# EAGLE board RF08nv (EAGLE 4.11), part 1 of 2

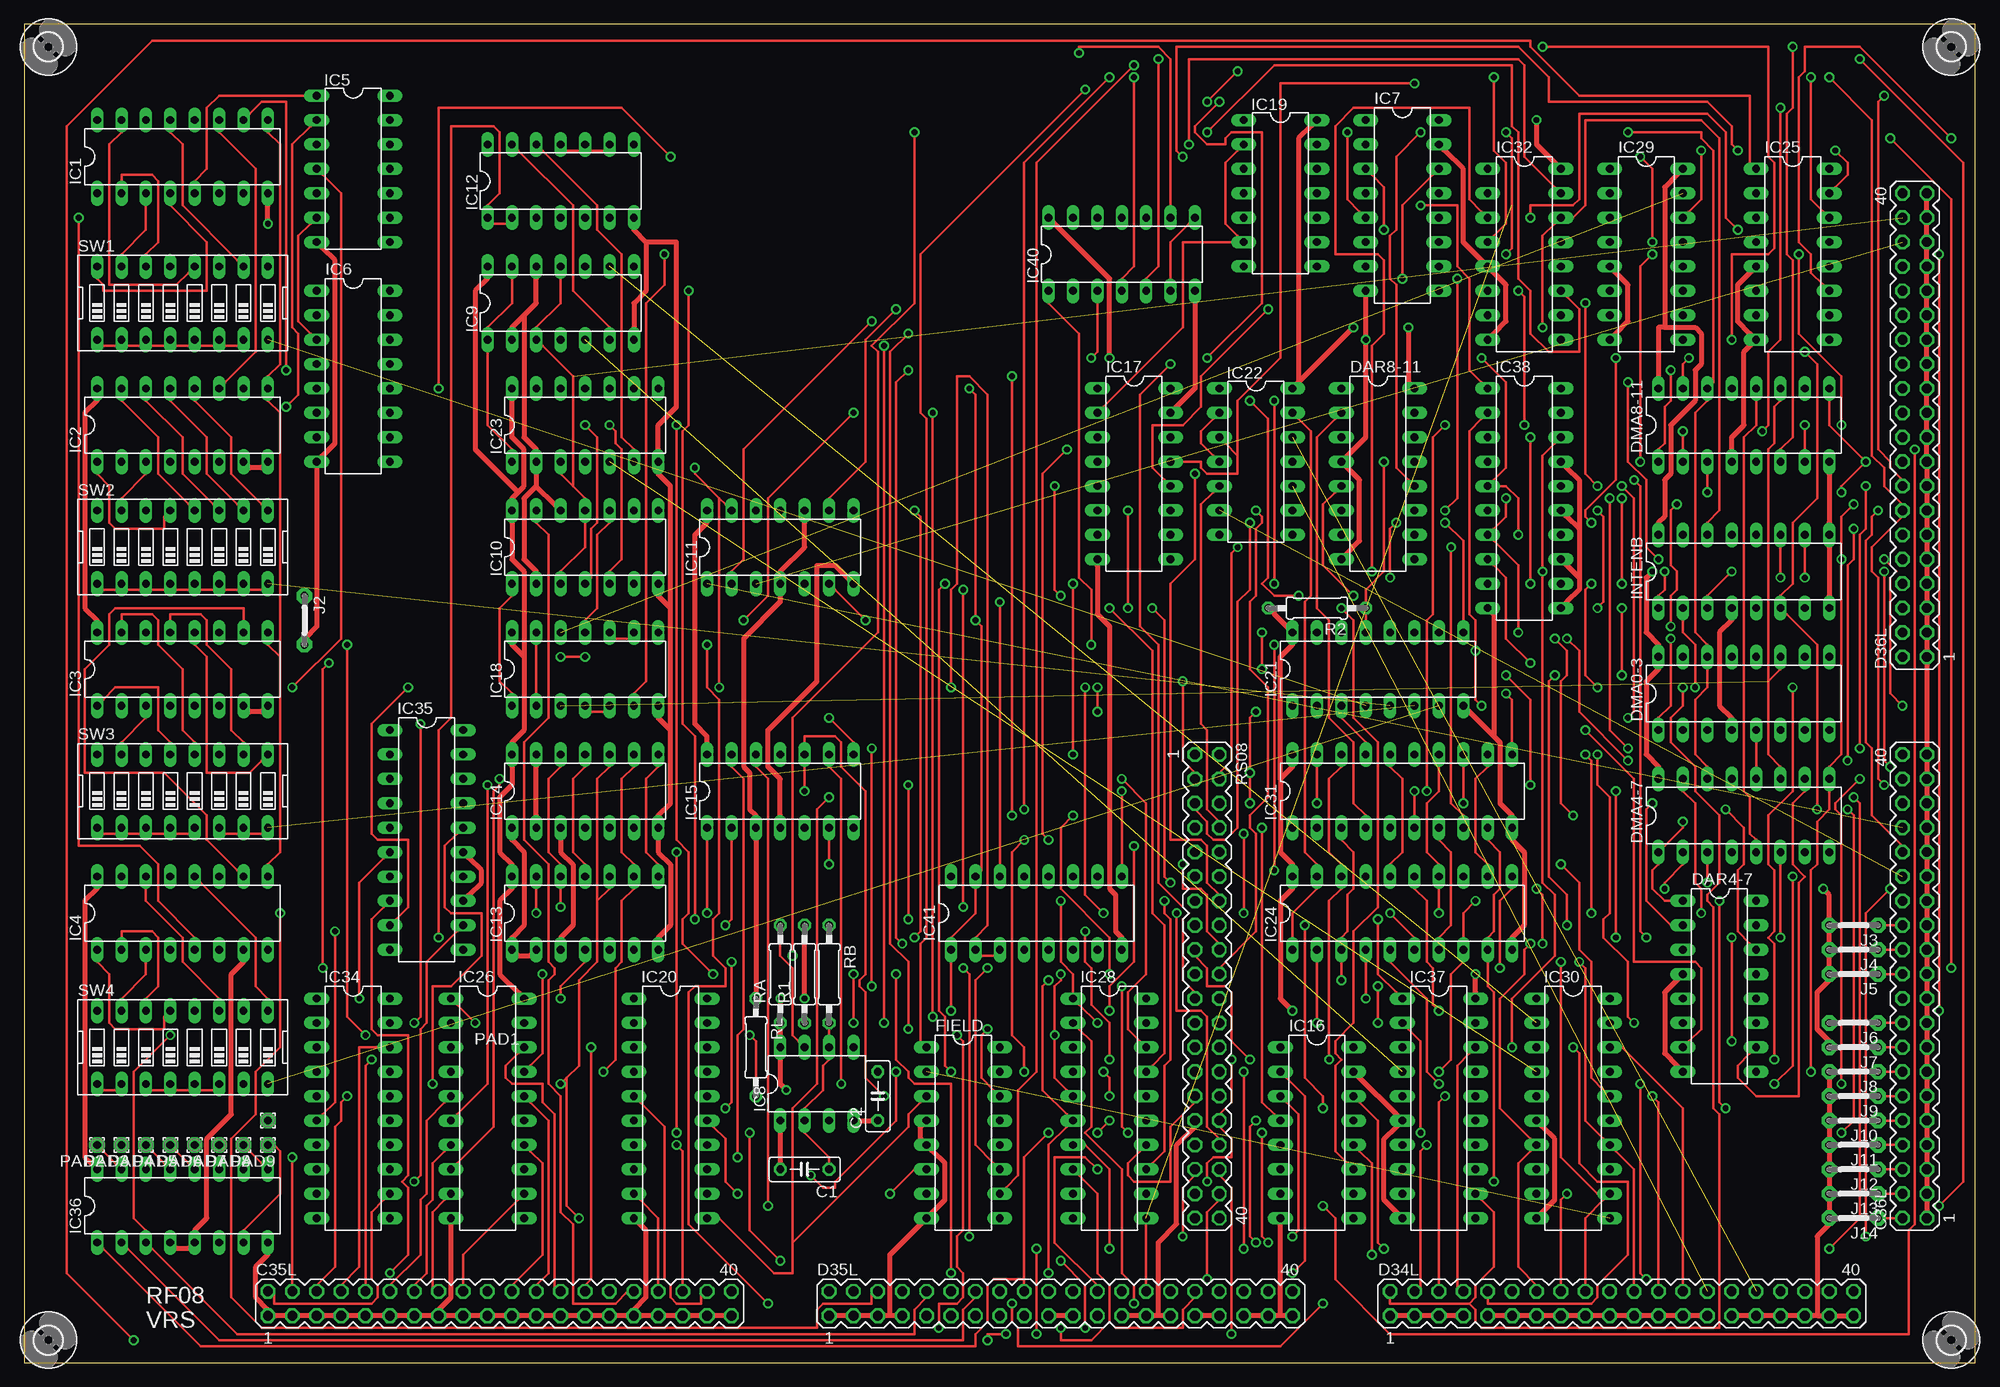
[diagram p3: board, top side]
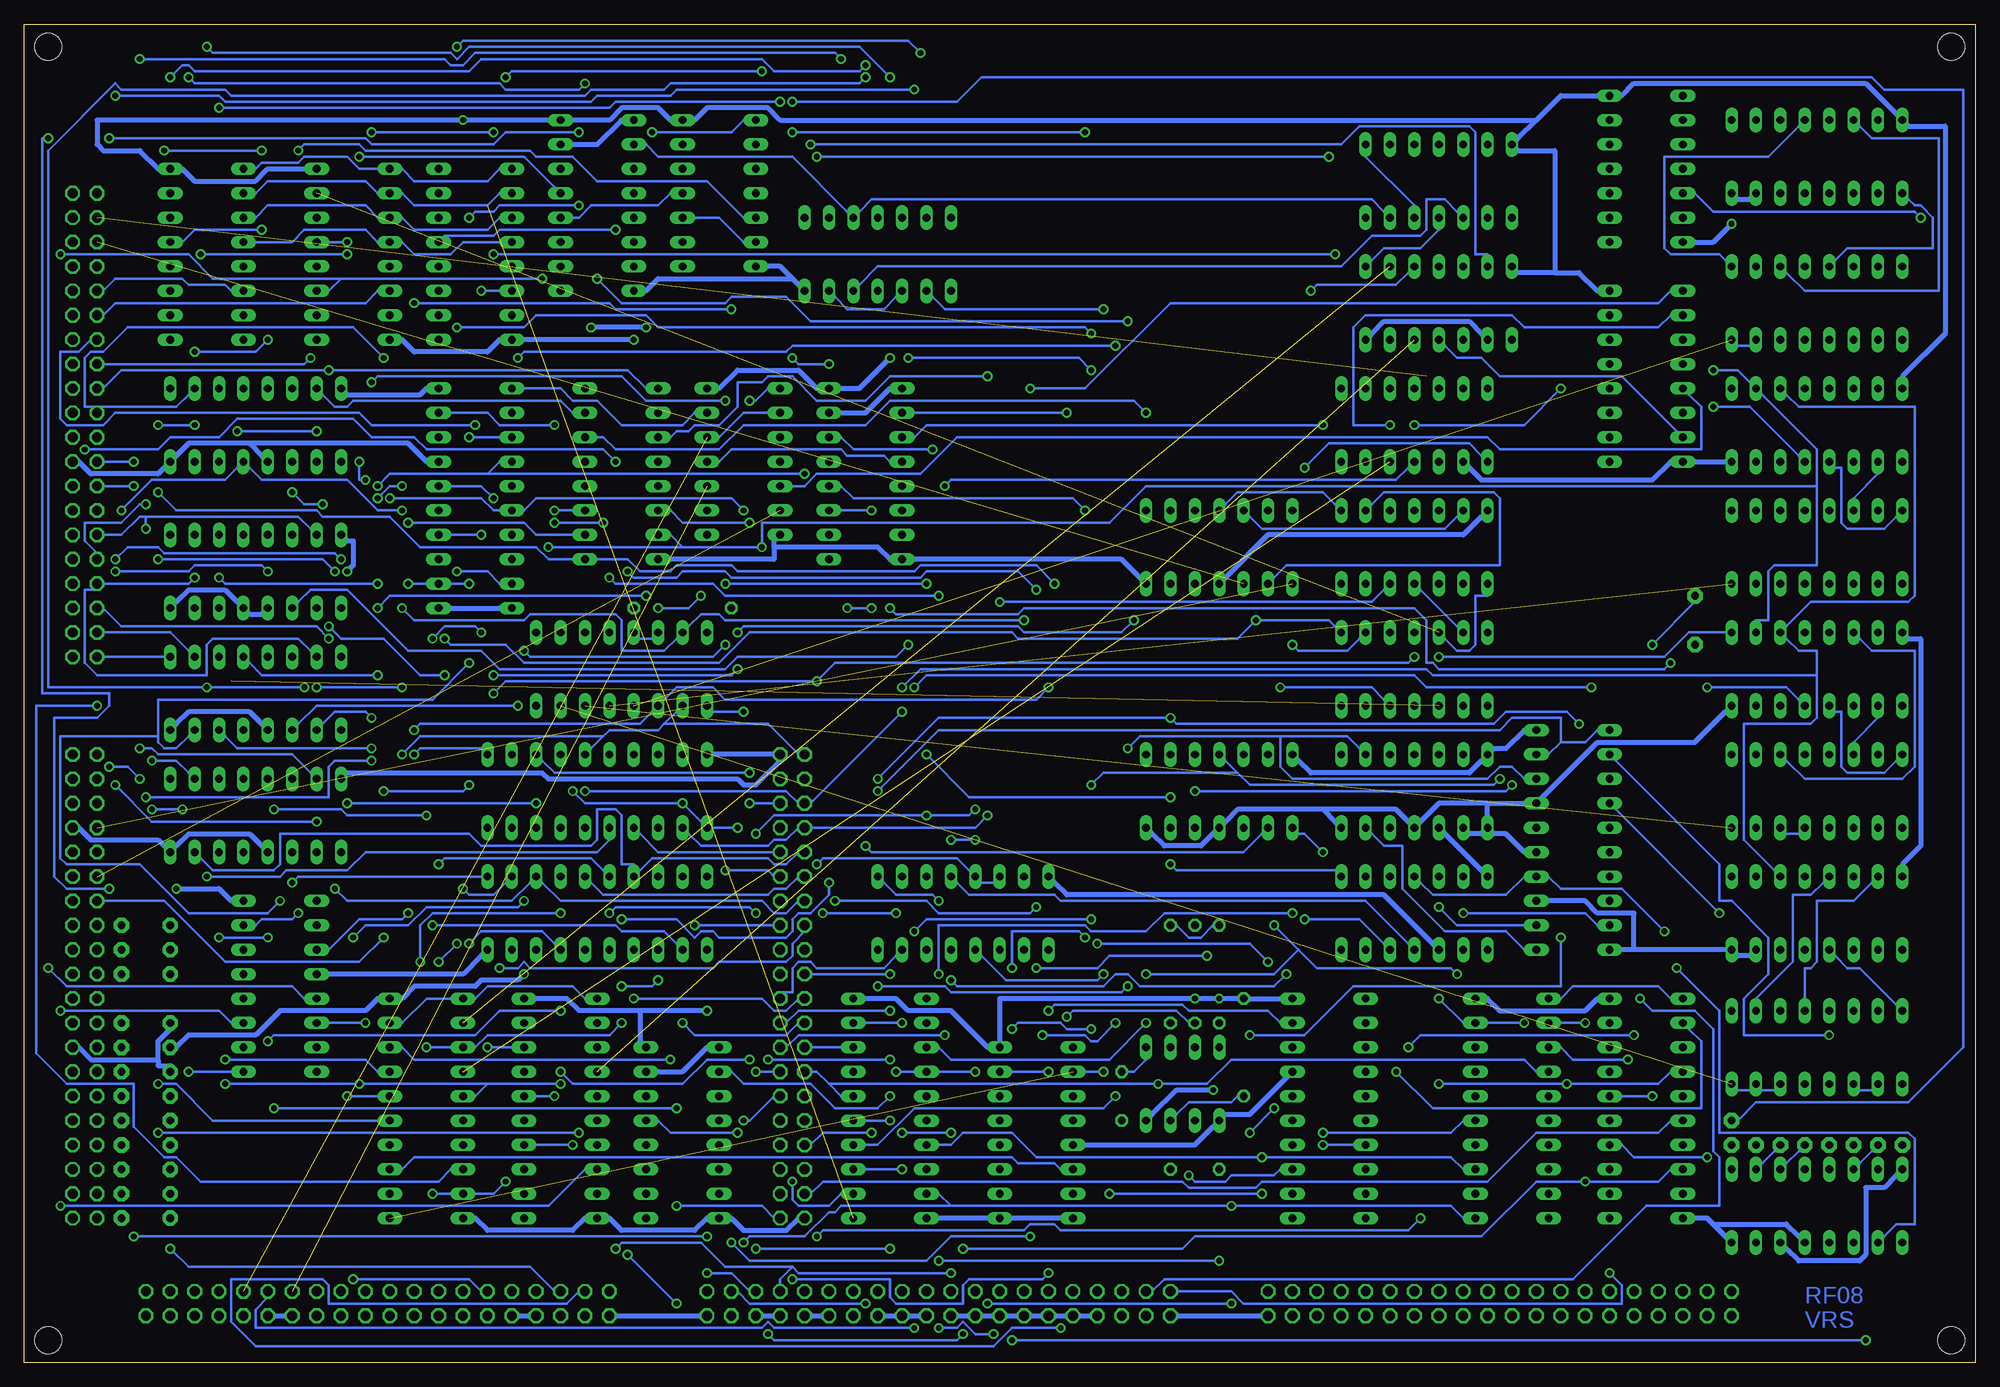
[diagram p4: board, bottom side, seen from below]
Size 203.18 x 139.37 mm. Coordinates in mm from the lower left corner, seen from the top.
Outline: 0,0 203.18,0 203.18,139.37 0,139.37 0,0
Copper layers (1*16): Top 0.035mm / dielectric 1.5mm / Bottom 0.035mm
Design rules "default": minimum track width 10mil, minimum drill 24mil, track to track 8mil, track to pad 8mil, pad to pad 8mil, via to via 8mil, smd to smd 8mil, copper to edge 40mil, drill to drill 8mil, minimum pad ring 10mil, minimum via ring 8mil, stop-mask expansion 4mil, vias tented up to drill 0mil, thermal gap 10mil
Net classes: 1 Power: width 0.508 mm

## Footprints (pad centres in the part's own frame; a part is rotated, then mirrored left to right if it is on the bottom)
C050-025X075 = drill 0.813 octagon: 1 -2.54,0; 2 2.54,0
MA20-2 = drill 1.016 octagon: 1 -24.13,-1.27; 2 -24.13,1.27; 3 -21.59,-1.27; 4 -21.59,1.27; 5 -19.05,-1.27; 6 -19.05,1.27; 7 -16.51,-1.27; 8 -16.51,1.27; 9 -13.97,-1.27; 10 -13.97,1.27; 11 -11.43,-1.27; 12 -11.43,1.27; 13 -8.89,-1.27; 14 -8.89,1.27; 15 -6.35,-1.27; 16 -6.35,1.27; 17 -3.81,-1.27; 18 -3.81,1.27; 19 -1.27,-1.27; 20 -1.27,1.27; 21 1.27,-1.27; 22 1.27,1.27; 23 3.81,-1.27; 24 3.81,1.27; 25 6.35,-1.27; 26 6.35,1.27; 27 8.89,-1.27; 28 8.89,1.27; 29 11.43,-1.27; 30 11.43,1.27; 31 13.97,-1.27; 32 13.97,1.27; 33 16.51,-1.27; 34 16.51,1.27; 35 19.05,-1.27; 36 19.05,1.27; 37 21.59,-1.27; 38 21.59,1.27; 39 24.13,-1.27; 40 24.13,1.27
DIL16 = drill 0.813 long: 1 -8.89,-3.81; 2 -6.35,-3.81; 3 -3.81,-3.81; 4 -1.27,-3.81; 5 1.27,-3.81; 6 3.81,-3.81; 7 6.35,-3.81; 8 8.89,-3.81; 9 8.89,3.81; 10 6.35,3.81; 11 3.81,3.81; 12 1.27,3.81; 13 -1.27,3.81; 14 -3.81,3.81; 15 -6.35,3.81; 16 -8.89,3.81
DIL14 = drill 0.813 long: 1 -7.62,-3.81; 2 -5.08,-3.81; 3 -2.54,-3.81; 4 0,-3.81; 5 2.54,-3.81; 6 5.08,-3.81; 7 7.62,-3.81; 8 7.62,3.81; 9 5.08,3.81; 10 2.54,3.81; 11 0,3.81; 12 -2.54,3.81; 13 -5.08,3.81; 14 -7.62,3.81
DIL08 = drill 0.813 long: 1 -3.81,-3.81; 2 -1.27,-3.81; 3 1.27,-3.81; 4 3.81,-3.81; 5 3.81,3.81; 6 1.27,3.81; 7 -1.27,3.81; 8 -3.81,3.81
DIL20 = drill 0.813 long: 1 -11.43,-3.81; 2 -8.89,-3.81; 3 -6.35,-3.81; 4 -3.81,-3.81; 5 -1.27,-3.81; 6 1.27,-3.81; 7 3.81,-3.81; 8 6.35,-3.81; 9 8.89,-3.81; 10 11.43,-3.81; 11 11.43,3.81; 12 8.89,3.81; 13 6.35,3.81; 14 3.81,3.81; 15 1.27,3.81; 16 -1.27,3.81; 17 -3.81,3.81; 18 -6.35,3.81; 19 -8.89,3.81; 20 -11.43,3.81
05 = drill 0.813 pad 1.6 octagon: 1 -2.54,0; 2 2.54,0
1,6/0,8 = drill 0.813 pad 1.6 octagon: 1 0,0
0207/10 = drill 0.813 octagon: 1 -5.08,0; 2 5.08,0
EDG-08 = drill 0.813 long: 1 -8.89,-3.81; 2 -6.35,-3.81; 3 -3.81,-3.81; 4 -1.27,-3.81; 5 1.27,-3.81; 6 3.81,-3.81; 7 6.35,-3.81; 8 8.89,-3.81; 9 8.89,3.81; 10 6.35,3.81; 11 3.81,3.81; 12 1.27,3.81; 13 -1.27,3.81; 14 -3.81,3.81; 15 -6.35,3.81; 16 -8.89,3.81
2,8 = hole 2.8: 0,0

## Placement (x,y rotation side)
C1  .1uf  [C050-025X075]  81.28,20.16 180 top
C2  .1uf  [C050-025X075]  88.9,27.78 90 top
C35L  [MA20-2]  49.52,6.18 0 top
C36L  [MA20-2]  196.84,39.2 90 top
D34L  [MA20-2]  166.37,6.18 0 top
D35L  [MA20-2]  107.95,6.18 0 top
D36L  [MA20-2]  196.84,97.62 90 top
DAR4-7  74LS193N  [DIL16]  176.53,39.2 270 top
DAR8-11  74LS193N  [DIL16]  140.97,92.54 270 top
DMA0-3  74LS193N  [DIL16]  179.06,69.68 0 top
DMA4-7  74LS193N  [DIL16]  179.06,56.98 0 top
DMA8-11  74LS193N  [DIL16]  179.06,97.62 0 top
FIELD  74LS193N  [DIL16]  97.79,23.96 270 top
IC1  74LS151N  [DIL16]  16.51,125.56 0 top
IC2  74LS151N  [DIL16]  16.51,97.62 0 top
IC3  74LS151N  [DIL16]  16.51,72.22 0 top
IC4  74LS151N  [DIL16]  16.51,46.83 0 top
IC5  74LS20N  [DIL14]  34.28,124.29 270 top
IC6  74S139N  [DIL16]  34.28,102.7 270 top
IC7  74LS139N  [DIL16]  143.5,120.48 270 top
IC8  LM555N  [DIL08]  82.55,29.05 0 top
IC9  74S74N  [DIL14]  55.88,110.32 0 top
IC10  74S74N  [DIL14]  58.41,84.92 0 top
IC11  74S74N  [DIL14]  78.73,84.92 0 top
IC12  74LS00N  [DIL14]  55.88,123.02 0 top
IC13  74180N  [DIL14]  58.41,46.83 0 top
IC14  74180N  [DIL14]  58.41,59.52 0 top
IC15  74180N  [DIL14]  78.73,59.52 0 top
IC16  74S139N  [DIL16]  134.62,23.96 270 top
IC17  74S139N  [DIL16]  115.56,92.54 270 top
IC18  74LS00N  [DIL14]  58.41,72.22 0 top
IC19  7407N  [DIL14]  130.81,121.75 270 top
IC20  74S240N  [DIL20]  67.31,26.51 270 top
IC21  74LS139N  [DIL16]  140.97,72.22 0 top
IC22  7407N  [DIL14]  128.27,93.81 270 top
IC23  74S74N  [DIL14]  58.41,97.62 0 top
IC24  74S240N  [DIL20]  143.5,46.83 0 top
IC25  74S138N  [DIL16]  184.15,115.4 270 top
IC26  74S240N  [DIL20]  48.25,26.51 270 top
IC28  74LS244N  [DIL20]  113.03,26.51 270 top
IC29  74S138N  [DIL16]  168.91,115.4 270 top
IC30  74S240N  [DIL20]  161.28,26.51 270 top
IC31  74S240N  [DIL20]  143.5,59.52 0 top
IC32  74S138N  [DIL16]  156.21,115.4 270 top
IC34  74S240N  [DIL20]  34.28,26.51 270 top
IC35  74LS244N  [DIL20]  41.9,54.45 270 top
IC36  74S138N  [DIL16]  16.51,16.35 0 top
IC37  74S240N  [DIL20]  147.31,26.51 270 top
IC38  74S240N  [DIL20]  156.21,90 270 top
IC40  74S03N  [DIL14]  114.3,115.4 0 top
IC41  74LS139N  [DIL16]  105.41,46.83 0 top
INTENB  74LS193N  [DIL16]  179.06,82.38 0 top
J2  J5MM  [05]  29.21,77.3 270 top
J3  J5MM  [05]  190.5,45.55 180 top
J4  J5MM  [05]  190.5,43.02 180 top
J5  J5MM  [05]  190.5,40.48 180 top
J6  J5MM  [05]  190.5,35.4 180 top
J7  J5MM  [05]  190.5,32.86 180 top
J8  J5MM  [05]  190.5,30.32 180 top
J9  J5MM  [05]  190.5,27.78 180 top
J10  J5MM  [05]  190.5,25.23 180 top
J11  J5MM  [05]  190.5,22.7 180 top
J12  J5MM  [05]  190.5,20.16 180 top
J13  J5MM  [05]  190.5,17.62 180 top
J14  J5MM  [05]  190.5,15.08 180 top
PAD1  [1,6/0,8]  25.39,25.23 90 top
PAD2  [1,6/0,8]  7.62,22.7 180 top
PAD3  [1,6/0,8]  10.15,22.7 180 top
PAD4  [1,6/0,8]  12.69,22.7 180 top
PAD5  [1,6/0,8]  15.23,22.7 180 top
PAD6  [1,6/0,8]  17.78,22.7 180 top
PAD7  [1,6/0,8]  20.32,22.7 180 top
PAD8  [1,6/0,8]  22.86,22.7 180 top
PAD9  [1,6/0,8]  25.39,22.7 180 top
R1  5.1K  [0207/10]  81.28,40.48 90 top
R2  5.1K  [0207/10]  134.62,78.57 180 top
RA  470K  [0207/10]  78.73,40.48 90 top
RB  1.5K  [0207/10]  83.81,40.48 270 top
RL  1K  [0207/10]  76.2,32.86 270 top
RS08  [MA20-2]  123.19,39.2 270 top
SW1  [EDG-08]  16.51,110.32 0 top
SW2  [EDG-08]  16.51,84.92 0 top
SW3  [EDG-08]  16.51,59.52 0 top
SW4  [EDG-08]  16.51,32.86 0 top
U$1  [2,8]  2.54,137 0 top
U$2  [2,8]  200.66,137 0 top
U$3  [2,8]  2.54,2.38 0 top
U$4  [2,8]  200.66,2.38 0 top

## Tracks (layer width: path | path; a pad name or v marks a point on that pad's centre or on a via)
3CYC\  (via drill 0.61)
  Top 0.254: v59.05,32.86 59.05,8.73 58.41,8.09 C35L.28 | v35.55,34.12 33.65,36.03 v33.65,74.77
  Bottom 0.254: v59.05,32.86 57.78,34.12 v35.55,34.12 | v33.65,74.77 29.21,79.21 J2.1
601\  (via drill 0.61)
  Top 0.254: IC18.4 59.05,67.78 60.32,67.78 IC18.5 | IC9.13 50.79,112.86 50.79,110.32 48.25,107.78 IC9.1 48.25,105.24 48.25,97.62 50.79,95.08 IC23.1 | 72.39,90 69.84,92.54 v69.84,93.18 | 72.39,90 73.02,89.37 IC11.13 | v121.28,126.83 121.28,135.72 155.57,135.72 156.21,135.09 156.21,125.56 159.38,122.39 IC32.15 | 72.39,90 v72.39,70.32
  Bottom 0.254: v69.84,93.18 67.31,95.72 52.7,95.72 51.43,94.45 IC23.1 | v121.28,126.83 66.04,126.83 64.13,128.74 52.7,128.74 52.06,128.11 52.06,115.4 50.79,115.4 IC9.13 | v72.39,70.32 62.86,70.32 61.59,69.05 IC18.5
602\  (1 unrouted)
  Top 0.254: IC18.1 50.79,69.68 49.52,70.95 49.52,78.57 50.79,79.84 IC10.1
  Bottom 0.254: IC18.12 55.24,75.4 53.97,74.13 52.7,74.13 52.06,74.77 52.06,79.84 50.79,79.84 IC10.1
604\  (via drill 0.61)
  Top 0.254: IC18.2 53.34,69.68 53.34,74.77 IC18.13 | v188.59,126.2 189.86,124.93 189.86,123.66 188.59,122.39 IC25.15 | v178.43,126.2 177.8,126.83 177.8,128.74 175.25,131.28 158.75,131.28 158.75,133.82 155.57,137 120.01,137 120.01,126.2 v120.65,125.56 | v67.31,125.56 62.22,130.65 43.17,130.65 v43.17,101.43 | v58.41,97.62 59.68,96.35 59.68,87.46 59.05,86.83 59.05,81.75 IC10.4
  Bottom 0.254: IC10.4 57.78,80.48 53.97,76.67 IC18.13 | v178.43,126.2 v188.59,126.2 | v120.65,125.56 v67.31,125.56 | v43.17,101.43 46.98,97.62 v58.41,97.62
611\  (via drill 0.61)
  Top 0.254: v100.33,34.76 99.69,34.12 99.69,29.68 100.96,28.41 FIELD.14 | v92.07,34.76 92.07,41.74 90.17,43.65 90.17,105.24 v92.07,107.15 | v158.11,107.78 158.11,117.31 159.38,118.58 IC32.14 161.28,119.21 162.56,120.48 162.56,129.38 174.62,129.38 176.53,127.47 176.53,88.73 175.25,87.46 INTENB.14
  Bottom 0.254: v100.33,34.76 99.69,35.4 95.25,35.4 94.61,34.76 v92.07,34.76 | v92.07,107.15 92.7,107.78 137.16,107.78 138.43,109.05 149.86,109.05 151.12,107.78 v158.11,107.78
612\  (via drill 0.61)
  Top 0.254: v174.62,126.2 174.62,121.12 173.35,119.85 IC29.14
  Bottom 0.254: v174.62,126.2 173.99,126.83 168.27,126.83 167.63,126.2 150.49,126.2 149.86,125.56 146.05,125.56 143.5,123.02 132.08,123.02 128.27,119.21 IC19.5
614\  (via drill 0.61)
  Top 0.254: 126.36,94.45 126.36,92.54 123.19,92.54 122.55,93.18 122.55,93.81 120.65,93.81 IC17.13 | 126.36,94.45 125.09,95.72 IC22.3 | v186.05,133.82 186.05,121.12 187.32,119.85 IC25.14 | v144.78,133.19 130.81,133.19 130.81,104.61 126.36,100.16 126.36,94.45
  Bottom 0.254: v186.05,133.82 185.41,133.19 153.66,133.19 153.03,132.55 145.41,132.55 v144.78,133.19
621\  (via drill 0.61)
  Top 0.254: v141.6,117.94 141.6,122.39 140.33,123.66 IC7.3
  Bottom 0.254: v141.6,117.94 153.66,117.94 154.3,117.31 159.38,117.31 IC32.13
622\  (via drill 0.61)
  Top 0.254: v168.27,125.56 169.54,124.29 v169.54,116.67
  Bottom 0.254: v168.27,125.56 151.12,125.56 147.95,122.39 IC7.13 | v169.54,116.67 171.44,116.67 IC29.13
624\  (via drill 0.61)
  Top 0.254: IC24.1 132.08,44.29 132.08,46.83 134.62,49.37 IC24.19 134.62,51.91 133.34,53.18 133.34,79.21 133.98,79.84 133.98,96.99 132.71,98.26 IC22.13 | v178.43,117.94 177.16,119.21 177.16,128.11 175.25,130.01 161.92,130.01 161.92,121.12 161.28,120.48 156.84,120.48 v156.84,119.21 | v145.41,120.48 149.22,120.48 149.22,114.13 150.49,112.86 150.49,103.34 151.76,102.07 IC38.1
  Bottom 0.254: IC22.13 133.34,98.89 134.62,97.62 140.97,97.62 143.5,100.16 146.05,100.16 147.31,101.43 151.12,101.43 IC38.1 | v178.43,117.94 185.41,117.94 186.69,116.67 IC25.13 | v156.84,119.21 156.21,119.85 154.3,119.85 153.66,120.48 v145.41,120.48
641\  (via drill 0.61)
  Top 0.254: v128.9,23.96 128.9,13.17 v129.53,12.54 | v98.42,13.17 98.42,40.48 v97.79,41.11 | v80.01,42.38 80.01,67.14 88.9,76.03 88.9,105.24 88.26,105.88 92.7,110.32 v92.7,128.11 | v123.19,128.11 130.17,135.09 154.94,135.09 154.94,128.74 155.57,128.11 155.57,112.86 156.84,111.59 156.84,107.15 158.75,105.24 161.92,105.24 161.92,109.69 160.65,110.96 IC32.11
  Bottom 0.254: v128.9,23.96 135.88,23.96 137.16,25.23 IC16.13 | v129.53,12.54 127.63,10.63 109.22,10.63 106.68,13.17 v98.42,13.17 | v97.79,41.11 91.44,41.11 90.17,42.38 v80.01,42.38 | v123.19,128.11 v92.7,128.11
642\  (via drill 0.61)
  Top 0.254: v147.95,88.73 149.22,90 v149.22,112.86 | v199.38,115.4 v199.38,36.66
  Bottom 0.254: v147.95,88.73 146.05,88.73 DAR8-11.11 | v149.22,112.86 170.18,112.86 | 170.18,112.86 171.44,111.59 IC29.11 | v199.38,36.66 182.88,36.66 181.61,35.4 DAR4-7.11 | v199.38,115.4 186.05,115.4 183.51,112.86 170.18,112.86
644\  (via drill 0.61)
  Top 0.254: v132.08,13.17 132.71,13.81 132.71,25.87 131.44,27.14 IC16.3 | v191.77,13.17 191.77,46.83 v194.31,49.37 | v200.66,127.47 191.13,137 185.41,137 185.41,134.46 184.78,133.82 184.78,116.67 186.05,115.4 186.05,113.5 187.32,112.23 IC25.11
  Bottom 0.254: v191.77,13.17 v132.08,13.17 | v194.31,49.37 198.75,49.37 200.02,50.63 200.02,67.14 195.58,67.14 194.31,68.41 194.31,69.68 201.29,69.68 201.29,127.47 v200.66,127.47
645\  (via drill 0.61)
  Top 0.254: v128.9,55.72 128.9,27.14 130.17,25.87 IC16.4 | v134.62,58.26 134.62,62.06 IC31.19 | v147.95,97.62 146.68,96.35 146.68,77.94 146.05,77.3 v146.05,59.52
  Bottom 0.254: v128.9,55.72 131.44,55.72 IC31.1 132.71,56.35 v134.62,58.26 144.78,58.26 v146.05,59.52 | v147.95,97.62 153.66,97.62 154.94,98.89 158.75,98.89 IC38.19
ACB00\  (via drill 0.61)
  Top 0.254: 150.49,6.18 151.12,6.82 151.12,8.09 153.03,10 153.03,15.71 151.76,16.98 IC37.12 | 150.49,6.18 142.24,6.18 142.24,6.82 D34L.2 | v156.84,81.11 v156.84,96.35 | 150.49,6.18 151.12,5.55 151.12,4.28 151.76,3.65 176.53,3.65 176.53,25.87 175.89,26.51 175.89,47.46 175.25,48.09 175.25,48.73 176.53,50 176.53,56.98 173.99,59.52 173.99,62.06 171.44,64.6 171.44,67.14 172.72,68.41 v172.72,70.32 | v163.83,70.32 162.56,71.59 162.56,80.48 v163.19,81.11
  Bottom 0.254: v156.84,81.11 158.75,81.11 IC38.12 161.28,81.11 v163.19,81.11 | v156.84,96.35 153.66,96.35 IC38.3 | v172.72,70.32 v163.83,70.32
ACB01\  (via drill 0.61)
  Top 0.254: v155.57,86.19 155.57,90 154.3,91.27 153.66,91.27 IC38.5 153.03,91.91 154.3,93.18 154.3,102.07 v151.76,104.61 | v146.05,22.7 145.41,22.06 145.41,7.46 D34L.4 | v89.53,105.88 v89.53,35.4 | v97.15,34.12 97.79,33.49 97.79,13.81 97.15,13.17 97.15,10 97.79,9.36 97.79,6.82 97.15,6.18 95.25,6.18 v95.25,3.65
  Bottom 0.254: v155.57,86.19 158.75,86.19 IC38.14 | v146.05,22.7 149.86,22.7 IC37.14 | v151.76,104.61 151.12,105.24 123.82,105.24 123.19,105.88 v89.53,105.88 | v89.53,35.4 91.44,33.49 92.07,33.49 92.7,34.12 v97.15,34.12 | v95.25,3.65 100.33,3.65 102.23,1.74 179.06,1.74 181.61,4.28 181.61,8.73 172.08,8.73 171.44,8.09 171.44,6.18 146.68,6.18 145.41,7.46 D34L.4
ACB02\  (via drill 0.61)
  Top 0.254: v154.3,90 154.3,88.1 153.03,86.83 IC38.7 153.03,85.56 155.57,83.02 v155.57,76.03 | v147.95,27.78 147.31,27.14 147.31,8.09 D34L.6 | v160.65,75.4 161.92,74.13 161.92,67.78 v167,62.7 | v190.5,58.89 191.13,58.26 191.13,15.08 v187.96,11.9
  Bottom 0.254: v154.3,90 155.57,91.27 158.75,91.27 IC38.16 | v147.95,27.78 149.86,27.78 IC37.16 | v155.57,76.03 156.21,76.67 159.38,76.67 v160.65,75.4 | v167,62.7 170.81,62.7 171.44,62.06 171.44,58.89 v190.5,58.89 | v187.96,11.9 186.05,10 150.49,10 147.95,7.46 D34L.6
ACB03\  (via drill 0.61)
  Top 0.254: IC38.18 159.38,95.72 158.11,94.45 v158.11,82.38 158.11,50 159.38,48.73 159.38,42.38 154.94,37.94 v154.94,32.86 | IC37.18 150.49,32.22 149.22,30.95 149.22,7.46 D34L.8
  Bottom 0.254: v158.11,82.38 154.94,82.38 153.66,81.11 IC38.9 | v154.94,32.86 152.4,32.86 IC37.18
ACB04\  (via drill 0.61)
  Top 0.254: IC31.3 137.16,54.45 138.43,53.18 138.43,49.37 137.79,48.73 137.79,44.92 137.16,44.29 IC24.3 137.16,41.74 v137.16,39.84 | v161.28,32.86 161.92,32.22 161.92,20.79 163.83,18.89 167,18.89 167,11.27 163.83,8.09 163.83,6.82 163.19,6.18 152.4,6.18 152.4,6.82 D34L.10 | v140.97,35.4 v140.97,39.2
  Bottom 0.254: v161.28,32.86 158.75,32.86 IC30.3 156.21,32.86 154.94,34.12 142.24,34.12 v140.97,35.4 | v137.16,39.84 137.79,39.2 v140.97,39.2
ACB05\  (via drill 0.61)
  Top 0.254: v147.31,29.05 146.05,30.32 146.05,37.94 142.24,41.74 IC24.5 | v184.15,50.63 184.15,30.95 v182.24,29.05 | v168.91,8.73 168.27,9.36 v168.27,29.05
  Bottom 0.254: 154.94,29.05 156.21,27.78 IC30.5 | 154.94,29.05 v147.31,29.05 | v184.15,50.63 176.53,50.63 175.89,51.27 169.54,51.27 167.63,53.18 143.5,53.18 142.24,54.45 IC31.5 | 154.94,29.05 v168.27,29.05 v182.24,29.05 | v168.91,8.73 156.84,8.73 155.57,7.46 D34L.12
ACB06\  (via drill 0.61)
  Top 0.254: IC24.7 147.31,44.29 148.59,45.55 148.59,53.18 147.31,54.45 IC31.7 | D34L.14 157.47,8.09 155.57,10 155.57,20.79 156.84,22.06 IC30.7 156.84,23.33 153.66,26.51 153.66,37.94 156.21,40.48 156.21,43.02 v156.84,43.65
  Bottom 0.254: v156.84,43.65 155.57,44.92 149.22,44.92 147.95,43.65 IC24.7
ACB07\  (via drill 0.61)
  Top 0.254: IC31.9 152.4,54.45 153.66,53.18 153.66,49.37 153.03,48.73 153.03,44.92 152.4,44.29 IC24.9 152.4,41.74 152.4,39.2 153.03,38.57 v153.03,18.89 | v160.65,17.62 160.02,16.98 160.02,8.09 D34L.16
  Bottom 0.254: v160.65,17.62 158.75,17.62 IC30.9 156.21,17.62 154.3,17.62 v153.03,18.89
ACB08\  (via drill 0.61)
  Top 0.254: IC24.12 152.4,51.91 151.12,53.18 151.12,60.8 152.4,62.06 IC31.12 | D34L.18 162.56,8.09 162.56,15.08 164.46,16.98 IC30.12 163.83,17.62 160.02,21.43 v160.02,41.74 | v157.47,49.37 158.11,48.73 v158.11,43.65
  Bottom 0.254: v157.47,49.37 156.84,48.73 154.3,48.73 153.03,50 IC24.12 | v160.02,41.74 v158.11,43.65
ACB09\  (via drill 0.61)
  Top 0.254: IC31.14 147.31,62.06 147.31,59.52 146.05,58.26 146.05,53.18 147.31,51.91 IC24.14 147.31,49.37 v147.31,46.83 | D34L.22 167.63,8.09 167.63,20.16 165.73,22.06 IC30.14 164.46,23.33 162.56,25.23 162.56,41.11 v161.92,41.74
  Bottom 0.254: v147.31,46.83 160.65,46.83 161.92,45.55 v161.92,41.74
ACB10\  (via drill 0.61)
  Top 0.254: IC24.16 142.24,51.91 143.5,53.18 143.5,60.8 142.24,62.06 IC31.16 | v169.54,27.78 170.18,27.14 170.18,8.09 D34L.24 | v160.02,51.91 161.92,50 161.92,43.02 163.19,41.74 163.19,29.68 164.46,28.41 IC30.16
  Bottom 0.254: v169.54,27.78 166.37,27.78 IC30.16 | v160.02,51.91 159.38,52.54 144.14,52.54 142.87,51.27 IC24.16
ACB11\  (via drill 0.61)
  Top 0.254: IC31.18 137.16,62.06 135.88,60.8 135.88,53.18 137.16,51.91 IC24.18 137.16,49.37 135.88,48.09 v135.88,31.59 | IC30.18 166.37,32.86 172.72,26.51 172.72,8.09 D34L.26
  Bottom 0.254: v135.88,31.59 162.56,31.59 163.83,32.86 IC30.18
ACCLEAR\  (1 unrouted)
  Top 0.254: IC22.4 123.82,94.45 122.55,95.72 122.55,96.99 123.82,98.26 IC22.2
  Bottom 0.254: IC22.12 130.81,96.35 128.27,98.89 125.73,98.89 IC22.2
BAC00
  Bottom 0.254: DMA0-3.9 188.59,73.49 194.94,73.49 D36L.2
BAC01
  Bottom 0.254: DMA0-3.10 186.05,74.13 187.96,76.03 194.94,76.03 D36L.4
BAC02  (via drill 0.61)
  Top 0.254: v171.44,75.4 171.44,68.41 170.18,67.14 DMA0-3.1
  Bottom 0.254: v171.44,75.4 172.72,76.67 193.03,76.67 194.94,78.57 D36L.6
BAC03  (via drill 0.61)
  Top 0.254: v185.41,81.75 185.41,84.92 INTENB.10
  Bottom 0.254: DMA0-3.15 173.35,74.13 174.62,75.4 183.51,75.4 184.15,74.77 184.15,71.59 195.58,71.59 196.84,72.86 196.84,80.48 195.58,80.48 D36L.8 194.94,81.11 186.05,81.11 v185.41,81.75
BAC04  (via drill 0.61)
  Top 0.254: v186.05,30.32 186.05,51.27 186.69,51.91 186.69,56.35 187.96,57.62 187.96,59.52 DMA4-7.9 187.96,62.06 189.22,63.34 v189.22,83.65 189.22,88.1 v190.5,89.37 | v170.81,82.38 170.81,80.48 170.18,79.84 INTENB.1
  Bottom 0.254: v186.05,30.32 181.61,30.32 DAR4-7.9 | v170.81,82.38 172.08,83.65 v189.22,83.65 | v190.5,89.37 191.13,89.37 193.03,87.46 196.84,87.46 196.84,85.56 195.58,84.29 D36L.10
BAC05  (via drill 0.61)
  Top 0.254: DAR4-7.10 179.7,32.22 178.43,30.95 178.43,29.68 180.34,27.78 184.78,27.78 184.78,50 185.41,50.63 184.15,51.91 184.15,58.26 185.41,59.52 DMA4-7.10 | v190.5,86.83 190.5,83.65 189.86,83.02 v189.86,62.7
  Bottom 0.254: 190.5,88.1 191.13,88.1 193.03,86.19 194.94,86.19 D36L.12 | 190.5,88.1 174.62,88.1 173.35,86.83 INTENB.15 | 190.5,88.1 v190.5,86.83 | v189.86,62.7 187.32,62.7 186.05,61.43 DMA4-7.10
BAC06  (via drill 0.61)
  Top 0.254: DAR4-7.1 171.44,48.09 170.81,48.09 169.54,49.37 169.54,51.27 170.18,51.91 DMA4-7.1 170.81,53.81 172.72,55.72 v172.72,56.35 | v115.56,135.09 105.41,124.93 105.41,30.32 103.5,28.41 103.5,19.52 102.23,18.25 FIELD.10 | v187.96,133.82 192.4,129.38 192.4,94.45 193.67,93.18 193.67,91.27 195.58,89.37 D36L.14 195.58,88.1 192.4,84.92 192.4,82.38 193.03,81.75 193.03,60.8 v193.67,60.16
  Bottom 0.254: v115.56,135.09 116.2,134.46 125.09,134.46 126.36,135.72 155.57,135.72 156.84,134.46 185.41,134.46 186.05,135.09 186.69,135.09 v187.96,133.82 | v172.72,56.35 189.86,56.35 v193.67,60.16
BAC07  (via drill 0.61)
  Top 0.254: v174.62,46.83 174.62,49.37 173.99,50 173.99,58.26 172.72,59.52 DMA4-7.15 | v110.48,132.55 93.34,115.4 93.34,98.89 93.98,98.26 93.98,44.29 93.34,43.65 93.34,33.49 FIELD.1 | v193.67,131.92 193.03,131.28 193.03,95.08 194.31,93.81 194.31,93.18 195.58,91.91 D36L.16 | v191.13,63.97 191.13,86.19 191.77,86.83 v191.77,91.27
  Bottom 0.254: v174.62,46.83 175.25,46.19 178.43,46.19 179.06,45.55 DAR4-7.15 | v110.48,132.55 135.25,132.55 135.88,131.92 143.5,131.92 144.14,131.28 182.24,131.28 182.88,131.92 v193.67,131.92 | v191.13,63.97 189.86,63.97 189.22,63.34 175.25,63.34 173.35,61.43 DMA4-7.15 | v191.77,91.27 194.94,91.27 D36L.16
BAC08  (via drill 0.61)
  Top 0.254: DMA8-11.9 187.96,100.16 187.96,97.62 v191.77,93.81 189.22,91.27 v189.22,90.64 | v96.52,30.32 95.88,30.95 95.88,36.03 95.25,36.66 95.25,80.48 v95.88,81.11
  Bottom 0.254: v191.77,93.81 194.94,93.81 D36L.18 | v96.52,30.32 100.33,30.32 FIELD.15 | v95.88,81.11 97.79,83.02 109.85,83.02 110.48,82.38 128.9,82.38 129.53,83.02 135.25,83.02 135.88,82.38 139.06,82.38 140.33,83.65 143.5,83.65 DAR8-11.9 146.05,83.65 148.59,83.65 149.86,84.92 161.92,84.92 165.09,88.1 172.08,88.1 172.72,88.73 187.32,88.73 v189.22,90.64
BAC09  (via drill 0.61)
  Top 0.254: v163.19,87.46 162.56,88.1 162.56,88.73 165.73,91.91 v165.73,104.61
  Bottom 0.254: v163.19,87.46 151.12,87.46 149.86,86.19 146.05,86.19 DAR8-11.10 | v165.73,104.61 168.91,107.78 192.4,107.78 194.94,105.24 196.21,105.24 196.84,104.61 196.84,99.53 195.58,99.53 | 195.58,99.53 D36L.22 195.58,99.53 | 195.58,99.53 187.32,99.53 186.05,100.8 DMA8-11.10
BAC10  (via drill 0.61)
  Top 0.254: v171.44,103.34 171.44,100.16 170.81,99.53 170.81,95.72 170.18,95.08 DMA8-11.1
  Bottom 0.254: D36L.24 194.94,101.43 193.03,103.34 v171.44,103.34 140.33,103.34 138.43,101.43 DAR8-11.1
BAC11  (via drill 0.61)
  Top 0.254: v173.35,104.61 172.72,103.97 172.72,102.7 DMA8-11.15
  Bottom 0.254: DAR8-11.15 146.05,98.89 147.31,100.16 168.91,100.16 169.54,99.53 170.81,99.53 172.08,100.8 DMA8-11.15 | v173.35,104.61 173.99,103.97 194.94,103.97 D36L.26
BADDAC\  (1 unrouted)
BBREAK\  (via drill 0.61)
  Top 0.254: v193.03,88.73 192.4,88.1 192.4,86.19 191.77,85.56 191.77,64.6 192.4,63.97 192.4,56.98 195.58,53.81 C36L.32 | v96.52,36.66 96.52,41.74 IC41.1 96.52,44.29 99.06,46.83 99.06,49.37 IC41.15 99.69,51.27 99.69,76.67 v99.06,77.3 99.06,100.8 v98.42,101.43 | v163.83,88.73 164.46,88.1 164.46,79.21 v163.83,78.57
  Bottom 0.254: v193.03,88.73 189.86,91.91 182.24,91.91 180.97,93.18 DMA8-11.5 179.7,93.18 178.43,91.91 169.54,91.91 166.37,88.73 v163.83,88.73 | v96.52,36.66 95.88,37.3 82.55,37.3 81.91,36.66 73.66,36.66 72.39,35.4 IC20.19 | v99.06,77.3 130.17,77.3 130.81,77.94 132.71,77.94 133.98,76.67 IC21.15 135.25,75.4 136.52,74.13 140.97,74.13 140.97,77.3 141.6,77.94 150.49,77.94 151.12,77.3 162.56,77.3 v163.83,78.57 | v98.42,101.43 92.7,101.43 83.81,110.32 33.02,110.32 31.75,111.59 IC6.1
BINIT  (1 unrouted)
  Top 0.254: IC9.11 55.88,112.86 55.88,110.32 53.34,107.78 IC9.3 53.97,105.88 57.14,102.7 57.14,91.27 | IC10.3 55.88,82.38 58.41,84.92 58.41,87.46 IC10.11 58.41,90 57.14,91.27 | 57.14,91.27 55.88,92.54 IC23.3
BIOP1  (via drill 0.61)
  Top 0.254: v155.57,111.59 156.21,110.96 v156.21,97.62
  Bottom 0.254: v155.57,111.59 153.66,111.59 IC32.6 | v156.21,97.62 167,97.62 168.27,98.89 193.67,98.89 194.94,97.62 198.75,97.62 199.38,98.26 199.38,105.24 197.48,105.24 196.21,106.52 D36L.28
BIOP2
  Bottom 0.254: IC29.6 166.37,111.59 167.63,110.32 193.67,110.32 194.94,109.05 D36L.30
BIOP4
  Bottom 0.254: IC25.6 181.61,111.59 182.24,112.23 186.05,112.23 186.69,112.86 193.67,112.86 194.94,111.59 D36L.32
BMB00  (via drill 0.61)
  Top 0.254: v38.09,9.36 40,11.27 40,18.25 39.36,18.89 40,19.52 40,34.12 36.82,34.12 36.19,34.76 36.19,46.19 37.46,47.46 IC35.8
  Bottom 0.254: v38.09,9.36 36.82,8.09 36.82,6.18 76.2,6.18 77.47,7.46 83.18,7.46 D35L.2
BMB01  (via drill 0.61)
  Top 0.254: v34.92,37.94 34.92,50 37.46,52.54 IC35.6
  Bottom 0.254: v34.92,37.94 33.65,36.66 29.21,36.66 27.3,34.76 27.3,22.06 26.67,21.43 26.67,16.35 34.28,16.35 41.9,8.73 84.45,8.73 85.72,7.46 D35L.4
BMB02  (via drill 0.61)
  Top 0.254: v26.67,46.83 26.67,32.86 24.12,30.32 24.12,25.87 21.59,23.33 21.59,6.82 24.76,3.65 82.55,3.65 82.55,5.55 83.18,6.18 88.26,6.18 88.26,7.46 D35L.6
  Bottom 0.254: v26.67,46.83 37.46,57.62 IC35.4
BMB03  (via drill 0.61)
  Top 0.254: D35L.10 93.98,6.82 92.7,5.55 92.7,3.01 22.22,3.01 13.33,11.9 IC36.3 12.69,13.81 11.42,15.08 11.42,30.32 v15.23,34.12
  Bottom 0.254: v15.23,34.12 24.12,34.12 24.12,37.94 21.59,40.48 21.59,44.29 25.39,48.09 26.67,48.09 26.67,51.91 37.46,62.7 IC35.2
BMB04  (via drill 0.61)
  Top 0.254: IC36.2 10.79,11.9 20.32,2.38 97.79,2.38 97.79,5.55 99.06,6.82 D35L.14 | v113.03,78.57 117.47,74.13 117.47,46.83 118.74,45.55 118.74,32.22 117.47,30.95 IC28.17 | v31.75,72.86 31.11,72.22 v31.11,41.11
  Bottom 0.254: v113.03,78.57 112.39,77.94 99.69,77.94 99.06,78.57 58.41,78.57 57.14,77.3 57.14,72.86 56.51,72.86 55.88,72.22 32.38,72.22 v31.75,72.86 | v31.11,41.11 26.67,36.66 26.67,23.96 6.98,23.96 6.34,23.33 6.34,14.44 8.25,14.44 9.52,13.17 IC36.2
BMB05  (via drill 0.61)
  Top 0.254: 104.14,8.73 100.96,8.73 100.33,8.09 100.33,4.28 99.06,3.01 99.06,1.74 18.41,1.74 8.25,11.9 IC36.1 | 104.14,8.73 104.14,8.09 D35L.18 | v111.76,23.96 v113.03,25.23 | v106.68,23.96 104.14,21.43 104.14,8.73
  Bottom 0.254: v113.03,25.23 115.56,25.23 IC28.15 | v106.68,23.96 v111.76,23.96
BMB06  (via drill 0.61)
  Top 0.254: v111.76,20.16 110.48,21.43 107.31,21.43 107.31,12.54 111.76,8.09 D35L.24 | v118.74,48.09 118.74,46.83 119.38,46.19 119.38,31.59 118.74,30.95 118.74,22.06 117.47,20.79 IC28.13 | v97.79,80.48 v97.79,47.46 | v140.33,82.38 140.33,105.88 141.6,107.15 141.6,114.77 140.97,115.4 136.52,115.4 136.52,128.74 138.43,130.65 150.49,130.65 150.49,121.12 151.76,119.85 IC32.3
  Bottom 0.254: v111.76,20.16 115.56,20.16 IC28.13 | IC32.3 153.66,119.21 154.94,117.94 162.56,117.94 163.83,119.21 IC29.3 166.37,119.21 167.63,120.48 177.8,120.48 179.06,119.21 IC25.3 | v118.74,48.09 109.22,48.09 107.95,46.83 98.42,46.83 v97.79,47.46 | v97.79,80.48 99.69,82.38 109.22,82.38 109.85,81.75 129.53,81.75 130.17,82.38 134.62,82.38 135.25,81.75 139.69,81.75 v140.33,82.38
BMB07  (1 unrouted)
  Top 0.254: IC28.11 116.84,14.44 116.84,8.09 D35L.28
  Bottom 0.254: IC32.2 153.66,121.75 154.94,120.48 162.56,120.48 163.83,121.75 IC29.2 166.37,121.75 167.63,123.02 177.8,123.02 179.06,121.75 IC25.2
BMB08  (via drill 0.61)
  Top 0.254: 113.03,4.28 113.03,8.09 111.76,9.36 111.76,17.62 109.85,19.52 IC28.8 | 113.03,4.28 113.66,3.65 120.65,3.65 120.65,5.55 121.92,6.82 D35L.32 | 113.03,4.28 111.12,2.38 107.95,2.38 v107.95,3.65 | v102.23,3.01 100.33,3.01 v100.33,2.38 | v11.42,2.38 4.44,9.36 4.44,128.74 13.33,137.63 156.84,137.63 156.84,137 161.92,131.92 179.7,131.92 179.7,124.93 IC25.1
  Bottom 0.254: IC32.1 153.66,124.29 154.94,123.02 162.56,123.02 163.83,124.29 IC29.1 166.37,124.29 168.27,124.29 169.54,125.56 173.99,125.56 174.62,124.93 178.43,124.93 179.06,124.29 IC25.1 | v107.95,3.65 106.04,3.65 105.41,4.28 104.14,3.01 v102.23,3.01 | v11.42,2.38 v100.33,2.38
BMB09  (via drill 0.61)
  Top 0.254: v106.68,9.36 106.68,22.7 108.58,24.6 IC28.6 108.58,25.87 106.04,28.41 106.04,39.2 v106.68,39.84 | v141.6,11.9 140.97,12.54 140.97,25.23 139.06,27.14 IC16.14 | v67.94,97.62 67.94,54.45 69.21,53.18 69.21,46.83 68.58,46.19 68.58,43.65 v71.75,40.48
  Bottom 0.254: v106.68,9.36 122.55,9.36 123.19,10 | 123.19,10 124.45,8.73 124.45,8.09 D35L.34 | v141.6,11.9 140.97,12.54 132.71,12.54 130.17,10 123.19,10 | v67.94,97.62 109.22,97.62 110.48,96.35 IC17.3 | v71.75,40.48 73.02,39.2 86.99,39.2 88.26,40.48 89.53,40.48 90.8,39.2 106.04,39.2 v106.68,39.84
BMB10  (via drill 0.61)
  Top 0.254: v112.39,30.32 113.03,29.68 v113.03,27.78 | v108.58,95.08 106.04,92.54 106.04,55.08 v106.68,54.45 | v104.14,54.45 102.87,53.18 102.87,34.12 104.14,32.86 v104.14,30.32 | v132.08,9.36 133.34,10.63 133.34,27.78 131.44,29.68 IC16.2
  Bottom 0.254: v112.39,30.32 110.48,30.32 IC28.4 107.95,30.32 v104.14,30.32 | v113.03,27.78 114.3,26.51 118.74,26.51 121.28,29.05 128.27,29.05 129.53,30.32 IC16.2 | v108.58,95.08 116.84,95.08 118.11,96.35 IC17.14 | v104.14,54.45 v106.68,54.45 | v132.08,9.36 129.53,9.36 127.63,7.46 D35L.36
BMB11  (via drill 0.61)
  Top 0.254: v115.56,6.18 115.56,8.09 114.3,9.36 114.3,20.16 110.48,23.96 111.12,24.6 111.12,33.49 109.85,34.76 IC28.2
  Bottom 0.254: v115.56,6.18 127.63,6.18 128.9,7.46 D35L.38
BRK_RQ\  (via drill 0.61)
  Top 0.254: v87.62,77.3 84.45,80.48 IC11.6 | v128.9,76.03 v128.9,72.22 | v154.3,71.59 156.84,69.05 v156.84,60.16 | v165.73,59.52 v165.73,44.29
  Bottom 0.254: v87.62,77.3 88.9,76.03 99.06,76.03 99.69,76.67 128.27,76.67 v128.9,76.03 | v128.9,72.22 129.53,71.59 v154.3,71.59 | v156.84,60.16 157.47,59.52 v165.73,59.52 | v165.73,44.29 168.27,41.74 182.24,41.74 188.59,48.09 194.94,48.09 C36L.28
BTS1  (1 unrouted)
BUSY  (via drill 0.61)
  Top 0.254: v143.5,112.86 143.5,120.48 146.68,123.66 IC7.14 | v88.26,108.42 74.93,95.08 74.93,83.65 73.66,82.38 IC11.2
  Bottom 0.254: IC10.9 62.86,89.37 61.59,90.64 50.16,90.64 49.52,90 49.52,83.02 71.75,83.02 73.02,81.75 IC11.2 | v143.5,112.86 140.97,110.32 130.17,110.32 129.53,110.96 123.82,110.96 121.28,108.42 v88.26,108.42
BWCO\
  Top 0.254: C35L.32 62.86,7.46 61.59,6.18 57.14,6.18 57.14,14.44 55.88,15.71 55.88,27.78 54.6,29.05 54.6,39.84 55.24,40.48 55.24,41.11 54.6,41.74 54.6,51.91 52.06,54.45 52.06,64.6 54.6,67.14 54.6,86.19 53.34,87.46 IC10.13
  Bottom 0.254: IC10.13 53.97,88.1 55.24,86.83 74.29,86.83 75.56,88.1 IC11.12
CIE  (via drill 0.61)
  Top 0.254: v189.22,29.05 189.22,56.98 188.59,57.62 188.59,58.26 v191.13,60.8 | v194.31,62.06 193.67,62.7 v193.67,82.38 | v177.8,82.38 175.25,79.84 INTENB.3 | v111.12,74.77 111.12,80.48 109.85,81.75 109.85,107.15 106.68,110.32 IC40.1
  Bottom 0.254: v189.22,29.05 187.32,29.05 183.51,25.23 166.37,25.23 IC30.15 | v191.13,60.8 192.4,62.06 v194.31,62.06 | v193.67,82.38 186.05,82.38 185.41,83.02 178.43,83.02 v177.8,82.38 | v111.12,74.77 112.39,73.49 128.9,73.49 130.17,72.22 153.66,72.22 155.57,74.13 163.19,74.13 169.54,80.48 173.35,80.48 174.62,79.21 INTENB.3
DA00\
  Top 0.254: C36L.2 194.94,15.08 193.67,15.08 J14.1
DA01\
  Top 0.254: C36L.4 194.94,17.62 193.67,17.62 J13.1
DA02\
  Top 0.254: C36L.6 194.94,20.16 193.67,20.16 J12.1
DA03\
  Top 0.254: C36L.8 194.94,22.7 193.67,22.7 J11.1
DA04\
  Top 0.254: C36L.10 194.94,25.23 193.67,25.23 J10.1
DA05\
  Top 0.254: C36L.12 194.94,27.78 193.67,27.78 J9.1
DA06\
  Top 0.254: C36L.14 194.94,30.32 193.67,30.32 J8.1
DA07\
  Top 0.254: C36L.16 194.94,32.86 193.67,32.86 J7.1
DA08\
  Top 0.254: C36L.18 194.94,35.4 193.67,35.4 J6.1
DA09\
  Top 0.254: C36L.22 194.94,40.48 193.67,40.48 J5.1
DA10\
  Top 0.254: C36L.24 194.94,43.02 193.67,43.02 J4.1
DA11\
  Top 0.254: C36L.26 194.94,45.55 193.67,45.55 J3.1
DAR04  (via drill 0.61)
  Top 0.254: IC41.3 100.96,42.38 99.69,42.38 IC41.2 99.06,44.29 100.33,45.55 100.33,100.8 98.42,102.7 97.15,102.7 97.15,81.11 96.52,80.48 v96.52,70.32 | IC21.3 137.16,67.14 139.69,64.6 IC31.17 | v162.56,65.88 167.63,60.8 167.63,41.74 173.99,41.74 174.62,41.11 174.62,34.76 173.35,33.49 DAR4-7.7
  Bottom 0.254: v162.56,65.88 161.92,66.51 139.06,66.51 137.79,67.78 IC21.3 136.52,69.05 135.25,70.32 131.44,70.32 130.17,69.05 97.79,69.05 v96.52,70.32
DAR05  (via drill 0.61)
  Top 0.254: v167.63,35.4 167,36.03 167,41.74 164.46,44.29 164.46,46.19 165.09,46.83 165.09,58.89 163.83,60.16 v163.83,63.34
  Bottom 0.254: 142.87,65.24 142.24,65.88 137.16,65.88 136.52,66.51 | 142.87,65.24 144.14,63.97 IC31.15 | 136.52,66.51 135.25,67.78 IC21.2 | v167.63,35.4 171.44,35.4 DAR4-7.6 | v163.83,63.34 161.92,65.24 142.87,65.24 | 136.52,66.51 125.73,66.51 122.55,63.34 RS08.1
DAR06  (via drill 0.61)
  Top 0.254: v128.27,67.78 127.63,67.14 v127.63,61.43 v127.63,58.26 | v169.54,58.26 168.91,57.62 168.91,48.09 171.44,45.55 DAR4-7.2 | v149.86,58.26 149.86,62.06 IC31.13
  Bottom 0.254: v128.27,67.78 131.44,67.78 IC21.1 | v127.63,58.26 125.09,58.26 RS08.6 | v127.63,61.43 147.95,61.43 149.22,62.7 IC31.13 | v149.86,58.26 v169.54,58.26
DAR07  (via drill 0.61)
  Top 0.254: v162.56,63.34 163.19,62.7 v163.19,46.83 | v120.65,70.95 120.65,62.7 121.92,61.43 RS08.3 | v154.3,69.68 154.94,69.05 154.94,64.6 IC31.11 | 26.67,73.49 26.67,53.18 25.39,51.91 IC4.9 | 26.67,73.49 25.39,74.77 IC3.9 | 26.67,73.49 26.67,98.89 25.39,100.16 IC2.9 25.39,102.7 26.67,103.97 26.67,126.83 25.39,128.11 IC1.9 | v55.88,73.49 v58.41,73.49
  Bottom 0.254: v162.56,63.34 161.92,63.97 155.57,63.97 IC31.11 | v163.19,46.83 163.83,46.19 168.27,46.19 171.44,43.02 DAR4-7.3 | v154.3,69.68 153.03,70.95 v120.65,70.95 118.74,72.86 59.05,72.86 v58.41,73.49 | v55.88,73.49 32.38,73.49 29.84,76.03 26.03,76.03 IC3.9
DAR08  (via drill 0.61)
  Top 0.254: v126.36,84.92 125.73,84.29 125.73,62.7 124.45,61.43 RS08.4 | v148.59,84.92 148.59,58.26 149.86,56.98 IC31.8 | IC4.10 22.22,51.27 19.05,54.45 19.05,56.98 14.6,61.43 6.34,61.43 6.34,72.22 8.88,74.77 8.88,77.94 9.52,78.57 22.86,78.57 22.86,77.3 IC3.10 | v27.3,103.34 27.3,131.28 24.76,131.28 23.49,130.01 IC1.10
  Bottom 0.254: 134.62,84.92 135.88,86.19 DAR8-11.7 | 134.62,84.92 v126.36,84.92 126.36,87.46 90.17,87.46 86.36,91.27 16.51,91.27 | 134.62,84.92 v148.59,84.92 | 16.51,91.27 16.51,83.02 20.95,83.02 21.59,82.38 21.59,77.3 22.86,77.3 IC3.10 | 16.51,91.27 16.51,95.08 22.22,100.8 IC2.10 23.49,102.07 24.76,103.34 v27.3,103.34
DAR09  (via drill 0.61)
  Top 0.254: v144.78,59.52 144.78,56.98 IC31.6 | v127.63,87.46 127.63,80.48 126.36,79.21 126.36,55.72 125.09,54.45 123.82,54.45 123.19,55.08 123.19,56.35 121.92,57.62 RS08.5 | IC2.11 20.95,102.07 24.12,105.24 24.12,124.29 20.32,128.11 IC1.11 | v111.76,70.32 v111.76,67.78
  Bottom 0.254: v144.78,59.52 123.82,59.52 122.55,58.26 RS08.5 121.28,58.26 v111.76,67.78 | v127.63,87.46 134.62,87.46 135.88,88.73 DAR8-11.6 | 16.51,71.59 16.51,74.13 18.41,74.13 19.68,75.4 IC3.11 19.68,76.67 17.14,79.21 6.98,79.21 6.34,79.84 6.34,99.53 18.41,99.53 19.68,100.8 IC2.11 | 16.51,71.59 16.51,67.14 17.14,66.51 24.12,66.51 24.12,54.45 20.95,51.27 IC4.11 | v111.76,70.32 109.85,72.22 57.14,72.22 56.51,71.59 16.51,71.59
DAR10
  Top 0.254: DAR8-11.2 136.52,98.26 134.62,96.35 134.62,78.57 135.88,77.3 135.88,67.14 138.43,64.6 138.43,58.26 139.69,56.98 IC31.4
  Bottom 0.254: IC31.4 139.06,55.08 137.16,53.18 125.09,53.18 RS08.10
DAR11  (via drill 0.61)
  Top 0.254: v102.87,56.98 v102.87,102.7
  Bottom 0.254: IC31.2 133.98,55.08 132.71,53.81 125.73,53.81 125.09,54.45 123.82,54.45 122.55,55.72 RS08.7 121.28,55.72 104.14,55.72 v102.87,56.98 | v102.87,102.7 113.03,102.7 115.56,100.16 120.65,100.16 123.19,102.7 125.73,102.7 126.36,102.07 128.9,102.07 128.9,99.53 130.81,97.62 133.34,97.62 133.98,96.99 135.25,96.99 135.88,96.35 DAR8-11.3
DATA00\
  Top 0.254: IC34.12 37.46,16.98 36.19,15.71 36.19,8.73 36.82,8.09 36.82,6.82 36.19,6.18 26.03,6.18 26.03,7.46 C35L.2
DATA01\  (via drill 0.61)
  Top 0.254: v27.94,21.43 27.94,8.09 C35L.4
  Bottom 0.254: v27.94,21.43 35.55,21.43 36.82,22.7 IC34.14
DATA02\  (via drill 0.61)
  Top 0.254: v33.65,27.78 33.02,27.14 33.02,25.23 32.38,24.6 32.38,10 30.48,8.09 C35L.6
  Bottom 0.254: v33.65,27.78 36.82,27.78 IC34.16
DATA03\
  Top 0.254: IC34.18 36.82,32.86 34.92,32.86 34.92,10 33.02,8.09 C35L.8
DATA04\  (via drill 0.61)
  Top 0.254: v36.19,31.59 35.55,30.95 35.55,8.09 C35L.10
  Bottom 0.254: v36.19,31.59 41.9,31.59 43.17,32.86 IC26.3
DATA05\
  Top 0.254: IC26.5 43.81,27.14 41.9,25.23 41.9,17.62 41.27,16.98 41.27,11.27 38.09,8.09 C35L.12
DATA06\
  Top 0.254: IC26.7 43.81,22.06 42.54,20.79 42.54,16.98 41.9,16.35 41.9,9.36 40.63,8.09 C35L.14
DATA07\
  Top 0.254: IC26.9 43.81,16.98 42.54,15.71 42.54,7.46 C35L.16
DATA08\
  Top 0.254: IC26.12 51.43,16.98 45.71,11.27 45.71,8.09 C35L.18
DATA09\
  Top 0.254: IC26.14 52.7,22.06 53.97,20.79 53.97,11.27 50.79,8.09 C35L.22
DATA10\
  Top 0.254: IC26.16 52.7,27.14 54.6,25.23 54.6,9.36 53.34,8.09 C35L.24
DATA11\
  Top 0.254: IC26.18 51.43,32.22 50.16,30.95 50.16,29.68 50.79,29.05 53.97,29.05 53.97,27.14 55.24,25.87 55.24,7.46 C35L.26
DATA_IN  (1 unrouted)
DCXA\  (via drill 0.61)
  Top 0.254: IC18.10 61.59,75.4 62.86,75.4 IC18.9 | v140.33,11.27 140.33,20.79 139.06,22.06 IC16.12 | v135.25,6.18 130.81,1.74 103.5,1.74 103.5,3.65 102.87,4.28 v102.87,6.18 | v77.47,6.18 69.21,14.44 69.21,38.57 69.84,39.2 73.02,39.2 73.02,41.11 71.75,42.38 71.75,46.19 72.39,46.83 72.39,69.05 71.12,70.32 v71.12,74.77
  Bottom 0.254: v135.25,6.18 v140.33,11.27 | v77.47,6.18 v102.87,6.18 | v71.12,74.77 70.48,74.13 65.4,74.13 64.13,75.4 IC18.9
DIMA\  (via drill 0.61)
  Top 0.254: v114.93,78.57 v114.93,88.73 | v117.47,78.57 118.74,77.3 118.74,50.63 v119.38,50 | v140.97,46.19 140.97,40.48 142.87,38.57 IC37.1
  Bottom 0.254: IC30.19 163.83,35.4 161.28,37.94 158.75,37.94 IC30.1 156.21,37.94 154.94,39.2 146.05,39.2 144.78,37.94 IC37.1 | v114.93,88.73 118.11,88.73 IC17.11 | v117.47,78.57 v114.93,78.57 | v119.38,50 119.38,48.73 121.28,46.83 122.55,46.83 123.19,46.19 123.19,44.92 123.82,44.29 130.81,44.29 131.44,44.92 132.71,44.92 133.34,44.29 135.25,46.19 v140.97,46.19
DIML\  (via drill 0.61)
  Top 0.254: v100.33,41.11 99.06,39.84 99.06,22.7 100.96,20.79 FIELD.11 | v92.7,44.29 93.34,44.92 93.34,88.1 v92.7,88.73 | v182.88,81.75 182.88,84.92 INTENB.11 | v166.37,90 v166.37,81.11 | v163.83,91.27 162.56,92.54 v162.56,110.32 | v129.53,109.69 122.55,102.7 122.55,99.53 120.65,97.62 117.47,97.62 117.47,93.18 118.74,91.91 IC17.12
  Bottom 0.254: v100.33,41.11 100.33,44.92 93.34,44.92 v92.7,44.29 | v92.7,88.73 93.98,90 116.84,90 118.11,91.27 IC17.12 | v182.88,81.75 182.24,81.11 v166.37,81.11 | v166.37,90 165.09,91.27 v163.83,91.27 | v162.56,110.32 142.24,110.32 141.6,109.69 v129.53,109.69
DIO00  (via drill 0.61)
  Top 0.254: IC14.12 55.88,62.06 54.6,60.8 54.6,53.18 55.88,51.91 IC13.12 55.88,49.37 v55.88,47.46 | v40.63,18.89 41.27,19.52 41.27,34.76 41.9,35.4 41.9,41.74 45.08,44.92 IC35.12 | v125.73,3.01 125.73,18.25 124.45,19.52 RS08.36 | v105.41,11.9 v105.41,3.01
  Bottom 0.254: IC34.8 31.75,20.16 33.02,18.89 v40.63,18.89 45.71,18.89 51.43,13.17 81.28,13.17 82.55,11.9 v105.41,11.9 | v125.73,3.01 125.09,2.38 106.04,2.38 v105.41,3.01 | v55.88,47.46 53.97,45.55 46.98,45.55 IC35.12
DIO01  (via drill 0.61)
  Top 0.254: IC13.11 58.41,51.91 57.14,53.18 57.14,60.8 58.41,62.06 IC14.11 | v32.38,44.92 32.38,27.14 31.11,25.87 IC34.6
  Bottom 0.254: v32.38,44.92 36.82,49.37 43.17,49.37 44.45,50.63 IC35.14 46.98,50.63 48.89,48.73 56.51,48.73 57.78,50 IC13.11 | RS08.37 121.28,17.62 120.01,18.89 82.55,18.89 81.91,18.25 74.93,18.25 74.29,18.89 50.79,18.89 45.71,23.96 33.02,23.96 31.75,25.23 IC34.6
DIO02  (via drill 0.61)
  Top 0.254: 56.51,29.68 57.78,30.95 57.78,39.84 59.68,41.74 59.68,48.09 | v55.88,29.05 56.51,29.68 | 59.68,48.09 60.95,49.37 IC13.10 | v42.54,29.05 42.54,39.2 44.45,39.2 47.62,42.38 47.62,46.83 44.45,46.83 43.81,47.46 43.81,53.81 45.08,55.08 IC35.16 | 59.68,48.09 59.68,60.8 60.95,62.06 IC14.10 | v120.65,13.17 120.65,18.25 121.92,19.52 RS08.35 | v57.78,15.08 56.51,16.35 56.51,29.68
  Bottom 0.254: v55.88,29.05 v42.54,29.05 33.02,29.05 31.75,30.32 IC34.4 | v120.65,13.17 120.01,13.81 99.06,13.81 98.42,14.44 95.88,14.44 95.25,13.81 59.05,13.81 v57.78,15.08
DIO03  (via drill 0.61)
  Top 0.254: v60.32,30.32 61.59,31.59 61.59,41.11 62.22,41.74 62.22,48.09 63.49,49.37 IC13.9 63.49,51.91 62.22,53.18 62.22,60.8 63.49,62.06 IC14.9 | v114.93,23.96 114.3,24.6 v114.3,39.2 | v88.26,63.97 v88.26,39.2
  Bottom 0.254: v60.32,30.32 56.51,26.51 28.57,26.51 28.57,33.49 29.84,34.76 IC34.2 | 72.39,65.24 72.39,62.06 71.12,60.8 50.79,60.8 49.52,62.06 48.25,62.06 46.98,60.8 IC35.18 | 72.39,65.24 65.4,65.24 64.13,63.97 IC14.9 | v114.93,23.96 120.01,23.96 121.28,22.7 RS08.33 | v114.3,39.2 107.31,39.2 106.68,38.57 88.9,38.57 v88.26,39.2 | v88.26,63.97 86.99,65.24 72.39,65.24
DIO04  (via drill 0.61)
  Top 0.254: v53.97,40.48 53.97,32.22 52.7,30.95 IC26.17 | v73.02,45.55 73.66,46.19 73.66,54.45 IC15.2 | v86.36,40.48 v86.36,35.4 | v113.03,36.66 113.03,39.2 115.56,41.74 v115.56,53.81
  Bottom 0.254: v53.97,40.48 54.6,41.11 68.58,41.11 70.48,43.02 | 70.48,43.02 v73.02,45.55 | v86.36,35.4 90.17,31.59 106.68,31.59 107.95,32.86 IC28.3 | v86.36,40.48 73.02,40.48 70.48,43.02 | v113.03,36.66 122.55,36.66 123.82,35.4 RS08.24 | v115.56,53.81 114.93,53.18 76.2,53.18 74.29,55.08 IC15.2
DIO05  (via drill 0.61)
  Top 0.254: IC28.5 108.58,28.41 107.31,29.68 v107.31,34.12 107.31,39.2 107.95,39.84 v107.95,40.48 | v67.94,23.96 v67.94,53.18 | v71.12,46.83 71.12,54.45 IC15.1
  Bottom 0.254: v107.31,34.12 122.55,34.12 123.82,32.86 RS08.26 | v67.94,23.96 54.6,23.96 53.34,25.23 IC26.15 | v67.94,53.18 69.84,55.08 70.48,55.08 IC15.1 | v107.95,40.48 107.95,45.55 92.7,45.55 92.07,44.92 86.36,44.92 84.45,46.83 v71.12,46.83
DIO06  (via drill 0.61)
  Top 0.254: v74.29,21.43 74.29,34.12 74.93,34.76 74.93,60.8 73.66,62.06 IC15.13 | v127,11.9 v127,30.32 | v113.03,11.9 113.03,20.16 110.48,22.7 IC28.7
  Bottom 0.254: IC26.13 53.34,20.16 54.6,21.43 v74.29,21.43 97.79,21.43 100.33,23.96 105.41,23.96 106.68,22.7 107.95,22.7 IC28.7 | v127,30.32 125.09,30.32 RS08.28 | v113.03,11.9 v127,11.9
DIO07  (via drill 0.61)
  Top 0.254: v77.47,16.35 77.47,60.8 76.2,62.06 IC15.12 | v128.27,25.23 127.63,24.6 127.63,13.17 v128.27,12.54
  Bottom 0.254: 106.68,16.35 v77.47,16.35 54.6,16.35 53.34,15.08 IC26.11 | 106.68,16.35 107.95,17.62 IC28.9 | v128.27,25.23 127.63,25.23 125.09,27.78 RS08.30 | v128.27,12.54 127.63,13.17 121.92,13.17 119.38,15.71 118.74,15.71 118.11,16.35 106.68,16.35
DIO08  (via drill 0.61)
  Top 0.254: v123.19,18.89 123.19,20.79 123.82,21.43 125.73,21.43 125.73,23.33 124.45,24.6 RS08.32 124.45,25.87 125.73,27.14 v125.73,31.59 | v49.52,60.8 49.52,60.16 48.89,59.52 48.89,24.6 45.08,20.79 IC26.8 | v113.03,31.59 113.03,35.4 111.12,37.3 111.12,41.11 110.48,41.74 v110.48,44.92 | v92.07,60.16 v92.07,46.19
  Bottom 0.254: v123.19,18.89 123.19,16.98 122.55,16.35 119.38,16.35 118.11,17.62 IC28.12 | v49.52,60.8 50.16,60.16 75.56,60.16 76.83,61.43 | 76.83,61.43 78.1,62.7 IC15.11 | v113.03,31.59 v125.73,31.59 | v110.48,44.92 109.22,46.19 v92.07,46.19 | v92.07,60.16 90.8,61.43 76.83,61.43
DIO09  (via drill 0.61)
  Top 0.254: IC28.14 116.2,22.06 114.93,20.79 114.93,19.52 115.56,18.89 119.38,18.89 119.38,24.6 121.92,27.14 RS08.29 | v48.25,60.16 48.25,29.05 45.08,25.87 IC26.6 | v81.28,59.52 81.28,62.06 IC15.10 81.28,64.6 81.28,65.24 84.45,65.24 85.09,64.6 85.09,62.06 87.62,59.52 87.62,40.48 86.99,39.84 86.99,39.2 87.62,38.57 87.62,29.68 v89.53,27.78
  Bottom 0.254: v48.25,60.16 48.89,59.52 v81.28,59.52 | v89.53,27.78 90.8,26.51 110.48,26.51 114.3,22.7 115.56,22.7 IC28.14
DIO10  (via drill 0.61)
  Top 0.254: v85.09,29.05 85.09,60.8 83.81,62.06 IC15.9
  Bottom 0.254: 119.38,29.05 120.65,30.32 121.28,30.32 RS08.27 | 119.38,29.05 118.11,27.78 IC28.16 | 119.38,29.05 v85.09,29.05 80.01,29.05 77.47,31.59 46.98,31.59 45.71,30.32 IC26.4
DIO11  (via drill 0.61)
  Top 0.254: v40.63,35.4 41.27,36.03 v41.27,66.51 | v83.81,67.14 86.36,64.6 IC15.8 | v114.3,60.8 116.84,58.26 116.84,40.48 114.93,38.57 114.93,34.76 116.2,33.49 IC28.18
  Bottom 0.254: IC28.18 118.11,32.86 121.28,32.86 RS08.25 | v40.63,35.4 43.17,35.4 IC26.2 | v41.27,66.51 42.54,67.78 48.89,67.78 50.16,66.51 83.18,66.51 v83.81,67.14 107.95,67.14 v114.3,60.8
DIOEVEN  (via drill 0.61)
  Top 0.254: v53.34,46.83 53.34,49.37 IC13.13 | v120.01,46.83 120.01,36.66 122.55,36.66 123.19,36.03 123.19,24.6 124.45,23.33 RS08.34 | v112.39,46.83 110.48,48.73 v110.48,70.32 | v40,70.32 36.19,66.51 36.19,55.08 36.82,54.45 40,54.45 40,47.46 38.73,46.19 IC35.9
  Bottom 0.254: v53.34,46.83 40.63,46.83 39.36,45.55 IC35.9 | v112.39,46.83 v120.01,46.83 | v110.48,70.32 109.22,71.59 58.41,71.59 57.14,70.32 v40,70.32
DMA00  (via drill 0.61)
  Top 0.254: v156.84,72.86 154.3,75.4 154.3,81.75 153.03,83.02 IC38.8 | v133.34,45.55 133.34,29.68 135.25,27.78 v135.25,26.51 | v177.16,26.51 176.53,27.14 v176.53,48.09
  Bottom 0.254: 189.22,65.24 189.22,69.05 160.65,69.05 v156.84,72.86 | 189.22,65.24 189.22,64.6 188.59,63.97 187.32,63.97 186.05,65.24 DMA0-3.7 | v133.34,45.55 125.09,45.55 RS08.16 | v177.16,26.51 v135.25,26.51 | v176.53,48.09 177.8,46.83 186.05,46.83 191.13,51.91 198.75,51.91 199.38,52.54 199.38,65.24 189.22,65.24
DMA01  (via drill 0.61)
  Top 0.254: v167,63.97 165.09,65.88 v165.09,90 | v128.27,88.73 128.9,88.1 128.9,87.46 128.27,86.83 128.27,79.84 127.63,79.21 127.63,72.22 129.53,70.32 129.53,58.89 127.63,56.98 127.63,55.72 128.27,55.08 128.27,44.92 124.45,41.11 RS08.20
  Bottom 0.254: v167,63.97 180.97,63.97 182.24,65.24 DMA0-3.6 | v165.09,90 155.57,90 154.3,88.73 153.66,88.73 IC38.6 151.12,88.73 149.86,90 129.53,90 v128.27,88.73
DMA02  (via drill 0.61)
  Top 0.254: v167,67.14 167.63,67.78 167.63,90 v166.37,91.27 | v121.92,92.54 121.92,83.65 119.38,81.11 119.38,54.45 122.55,54.45 123.19,53.81 123.19,50 124.45,48.73 RS08.14
  Bottom 0.254: v167,67.14 167.63,67.78 170.81,67.78 172.08,66.51 DMA0-3.2 | v166.37,91.27 165.09,92.54 154.94,92.54 | 154.94,92.54 153.66,93.81 IC38.4 | 154.94,92.54 v121.92,92.54
DMA03  (via drill 0.61)
  Top 0.254: v151.76,68.41 151.12,69.05 v151.12,74.13 151.12,77.3 150.49,77.94 150.49,96.99 151.76,98.26 IC38.2 | v130.17,51.27 v130.17,74.77
  Bottom 0.254: v151.76,68.41 172.72,68.41 174.62,66.51 DMA0-3.3 | v130.17,51.27 125.73,51.27 125.09,50.63 RS08.12 | v130.17,74.77 131.44,73.49 150.49,73.49 v151.12,74.13
DMA04
  Bottom 0.254: RS08.9 122.55,53.18 123.82,51.91 125.09,51.91 125.73,52.54 137.79,52.54 139.06,51.27 IC24.17 139.69,51.91 140.97,51.91 140.97,56.98 141.6,57.62 143.5,57.62 143.5,54.45 144.14,53.81 155.57,53.81 156.84,55.08 176.53,55.08 176.53,51.91 177.16,51.27 183.51,51.27 184.78,52.54 DMA4-7.7
DMA05  (via drill 0.61)
  Top 0.254: v182.88,44.29 182.88,51.91 DMA4-7.6 | v177.8,33.49 v177.8,44.29 | v147.31,36.66 146.68,37.3 146.68,41.11 146.05,41.74 146.05,48.09 144.78,49.37 IC24.15
  Bottom 0.254: IC24.15 144.14,50 142.87,48.73 125.73,48.73 125.09,49.37 123.82,49.37 122.55,50.63 RS08.11 | v177.8,44.29 v182.88,44.29 | v177.8,33.49 177.16,34.12 156.21,34.12 153.66,36.66 v147.31,36.66
DMA06  (via drill 0.61)
  Top 0.254: v170.81,49.37 170.81,50 172.72,51.91 DMA4-7.2
  Bottom 0.254: RS08.13 122.55,48.09 123.82,46.83 125.09,46.83 126.36,48.09 147.31,48.09 149.22,50 IC24.13 150.49,50 152.4,48.09 169.54,48.09 v170.81,49.37
DMA07  (via drill 0.61)
  Top 0.254: v175.25,50 175.25,51.91 DMA4-7.3 | v153.66,41.11 153.66,48.09 154.94,49.37 IC24.11
  Bottom 0.254: v175.25,50 174.62,50.63 155.57,50.63 IC24.11 | v153.66,41.11 151.76,41.11 151.12,41.74 150.49,41.11 131.44,41.11 130.81,41.74 123.82,41.74 123.19,42.38 123.19,43.65 121.92,44.92 RS08.15
DMA08  (via drill 0.61)
  Top 0.254: v147.31,30.32 148.59,31.59 148.59,40.48 149.86,41.74 IC24.8 149.86,44.29 149.86,46.83 v151.12,48.09 | v127.63,31.59 125.73,33.49 125.73,38.57 125.09,39.2 123.19,39.2 123.19,41.11 121.92,42.38 RS08.17 | v185.41,97.62 185.41,95.08 DMA8-11.7 | v189.22,97.62 189.22,102.7 184.78,107.15 v184.78,115.4 | v169.54,115.4 168.27,114.13 v168.27,93.81 | v167.63,91.91 168.27,91.27 168.27,44.92 v168.91,44.29
  Bottom 0.254: v147.31,30.32 146.05,29.05 134.62,29.05 132.08,31.59 v127.63,31.59 | v189.22,97.62 v185.41,97.62 | v169.54,115.4 v184.78,115.4 | v168.27,93.81 168.27,91.91 v167.63,91.91 | v168.91,44.29 167.63,45.55 163.19,45.55 161.28,47.46 151.76,47.46 v151.12,48.09
DMA09  (via drill 0.61)
  Top 0.254: v142.24,46.83 144.78,44.29 IC24.6 | v127,55.08 v127,46.83 | v109.22,56.98 107.95,55.72 107.95,49.37 113.03,44.29 v113.03,40.48 | v184.15,137 184.15,130.65 183.51,130.01 183.51,115.4 184.15,114.77 184.15,96.35 182.88,95.08 DMA8-11.6 | v113.03,133.82 104.14,124.93 v104.14,57.62
  Bottom 0.254: v142.24,46.83 141.6,47.46 127.63,47.46 v127,46.83 | v127,55.08 125.09,56.98 v109.22,56.98 104.77,56.98 v104.14,57.62 | v113.03,40.48 121.28,40.48 RS08.19 | v184.15,137 183.51,136.36 158.75,136.36 158.11,135.72 156.84,137 116.2,137 v113.03,133.82
DMA10  (via drill 0.61)
  Top 0.254: v139.69,37.94 139.69,41.74 IC24.4 | v172.72,96.99 172.72,95.08 DMA8-11.2 | v180.97,96.99 181.61,97.62 181.61,105.24 182.88,106.52 v182.88,130.65 | v124.45,131.28 121.92,128.74 121.92,128.11 123.19,126.83 125.09,126.83 125.09,127.47 125.73,128.11 128.9,128.11 128.9,110.32 v123.19,104.61 | v119.38,103.97 116.2,100.8 116.2,76.67 118.11,74.77 118.11,50 121.28,46.83 120.65,46.19 120.65,39.84 121.92,38.57 RS08.21
  Bottom 0.254: v139.69,37.94 126.36,37.94 125.09,36.66 123.82,36.66 122.55,37.94 RS08.21 | v180.97,96.99 v172.72,96.99 | v182.88,130.65 142.24,130.65 141.6,131.28 v124.45,131.28 | v123.19,104.61 122.55,103.97 v119.38,103.97
DMA11  (via drill 0.61)
  Top 0.254: v134.62,35.4 134.62,41.74 IC24.2 | v175.25,90.64 175.25,92.54 DMA8-11.3 | v172.08,89.37 171.44,88.73 171.44,83.02 172.08,82.38 172.08,80.48 171.44,79.84 v171.44,76.67 | v159.38,71.59 158.75,70.95 158.75,50.63 160.65,48.73 v160.65,45.55
  Bottom 0.254: v134.62,35.4 133.34,34.12 123.82,34.12 122.55,35.4 RS08.23 | v175.25,90.64 173.99,89.37 v172.08,89.37 | v171.44,76.67 170.18,75.4 165.73,75.4 161.92,71.59 v159.38,71.59 | v160.65,45.55 141.6,45.55 140.97,44.92 136.52,44.92 135.25,43.65 IC24.2
DMA-IN\  (via drill 0.61)
  Top 0.254: v46.98,35.4 45.08,37.3 IC26.1 | v55.88,37.94 55.88,39.2 58.41,41.74 IC13.4
  Bottom 0.254: IC34.1 31.75,37.94 33.02,39.2 41.9,39.2 43.17,37.94 IC26.1 | v46.98,35.4 50.79,35.4 IC26.19 53.34,35.4 v55.88,37.94 | IC41.12 106.04,50 104.77,48.73 95.88,48.73 95.25,48.09 63.49,48.09 59.05,43.65 IC13.4
DMA-OUT\  (via drill 0.61)
  Top 0.254: v111.76,35.4 109.85,37.3 IC28.1 109.22,38.57 109.22,40.48 107.95,41.74 v107.95,48.09 | v114.3,59.52 114.3,51.91 IC41.9
  Bottom 0.254: 43.17,64.6 44.45,63.34 IC35.19 | 43.17,64.6 40.63,64.6 39.36,65.88 IC35.1 | v111.76,35.4 115.56,35.4 IC28.19 | v107.95,48.09 108.58,48.73 112.39,48.73 113.66,50 IC41.9 | 43.17,64.6 43.17,67.14 48.25,67.14 49.52,65.88 107.95,65.88 v114.3,59.52
DONE  (via drill 0.61)
  Top 0.254: v90.8,109.69 87.62,106.52 87.62,93.81 83.81,90 IC11.9
  Bottom 0.254: v90.8,109.69 107.31,109.69 108.58,110.96 IC40.2
DRV01\  (via drill 0.61)
  Top 0.254: v90.8,40.48 90.8,31.59 92.07,30.32 92.07,29.68 92.7,29.05 96.52,29.05 v96.52,9.36 | v123.19,8.73 123.19,15.71 124.45,16.98 RS08.38
  Bottom 0.254: v90.8,40.48 91.44,39.84 100.96,39.84 103.5,42.38 IC41.4 | v96.52,9.36 97.15,8.73 104.77,8.73 105.41,8.09 105.41,6.18 112.39,6.18 113.03,6.82 113.03,8.73 v123.19,8.73
DRV23\
  Bottom 0.254: IC41.7 112.39,42.38 113.66,41.11 120.65,41.11 121.28,41.74 122.55,41.74 123.19,41.11 123.19,38.57 124.45,38.57 RS08.22
DRVOK\  (via drill 0.61)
